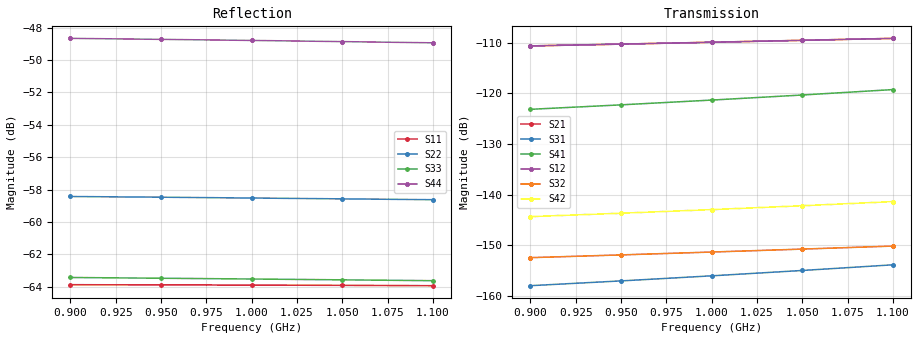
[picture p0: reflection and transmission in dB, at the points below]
! Touchstone file exported from HFSS 2020.2.0
!  Generated:  11:13:08  avr. 27, 2020
!  Design:  test
!  Project:  test_multiport
!  Setup:  Setup1
!  Solution:  Sweep
!Data is not renormalized
# GHZ S MA
! Terminal data exported
! Port[1] = 1
! Port[2] = 2
! Port[3] = 3
! Port[4] = 4
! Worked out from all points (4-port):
!   5 points, 900 MHz to 1.1 GHz, reference per port
!   strongest paths, dB at 900 MHz, 950 MHz, 1 GHz, 1.05 GHz, 1.1 GHz:
!     S21: -110.6, -110.3, -109.9, -109.5, -109.1
!     S41: -123.2, -122.3, -121.3, -120.3, -119.3
!     S42: -144.3, -143.7, -143.0, -142.2, -141.4
!     S32: -152.4, -151.9, -151.3, -150.8, -150.2
!     S31: -158.0, -157.0, -156.0, -155.0, -153.9
!     S43: -165.9, -164.8, -163.7, -162.4, -161.1
!   lowest |S11| = -63.9 dB at 1.1 GHz (marker M1), VSWR 1.00
!   |S11| at or under -10 dB: start of sweep to end of sweep
0.9  0.0006406 180.0  2.941e-06 0.0  1.262e-08 -0.0  6.956e-07 -0.0
     2.941e-06 0.0  0.001199 180.0  2.387e-08 -180.0  6.067e-08 -180.0
     1.262e-08 -0.0  2.387e-08 180.0  0.0006743 -180.0  5.092e-09 -0.0
     6.956e-07 0.0  6.067e-08 180.0  5.092e-09 -0.0  0.003689 -180.0
0.95  0.0006398 180.0  3.063e-06 0.0  1.407e-08 -0.0  7.7e-07 -0.0
      3.063e-06 0.0  0.001193 180.0  2.541e-08 -180.0  6.554e-08 -180.0
      1.407e-08 -0.0  2.541e-08 -180.0  0.0006707 180.0  5.759e-09 -0.0
      7.7e-07 -0.0  6.554e-08 -180.0  5.759e-09 -0.0  0.003663 180.0
1  0.0006388 -180.0  3.196e-06 -0.0  1.579e-08 -0.0  8.583e-07 -0.0
   3.196e-06 -0.0  0.001186 -180.0  2.712e-08 -180.0  7.117e-08 180.0
   1.579e-08 -0.0  2.712e-08 -180.0  0.000667 -180.0  6.568e-09 0.0
   8.583e-07 -0.0  7.117e-08 -180.0  6.568e-09 0.0  0.003635 180.0
1.05  0.0006376 -180.0  3.339e-06 -0.0  1.784e-08 -0.0  9.635e-07 -0.0
      3.339e-06 -0.0  0.001179 -180.0  2.9e-08 180.0  7.772e-08 180.0
      1.784e-08 -0.0  2.9e-08 180.0  0.0006631 -180.0  7.556e-09 0.0
      9.635e-07 -0.0  7.772e-08 180.0  7.556e-09 0.0  0.003605 180.0
1.1  0.0006361 180.0  3.491e-06 -0.0  2.029e-08 0.0  1.09e-06 0.0
     3.491e-06 -0.0  0.001172 180.0  3.107e-08 -180.0  8.538e-08 -180.0
     2.029e-08 0.0  3.107e-08 -180.0  0.0006591 180.0  8.771e-09 0.0
     1.09e-06 0.0  8.538e-08 -180.0  8.771e-09 0.0  0.003574 180.0
